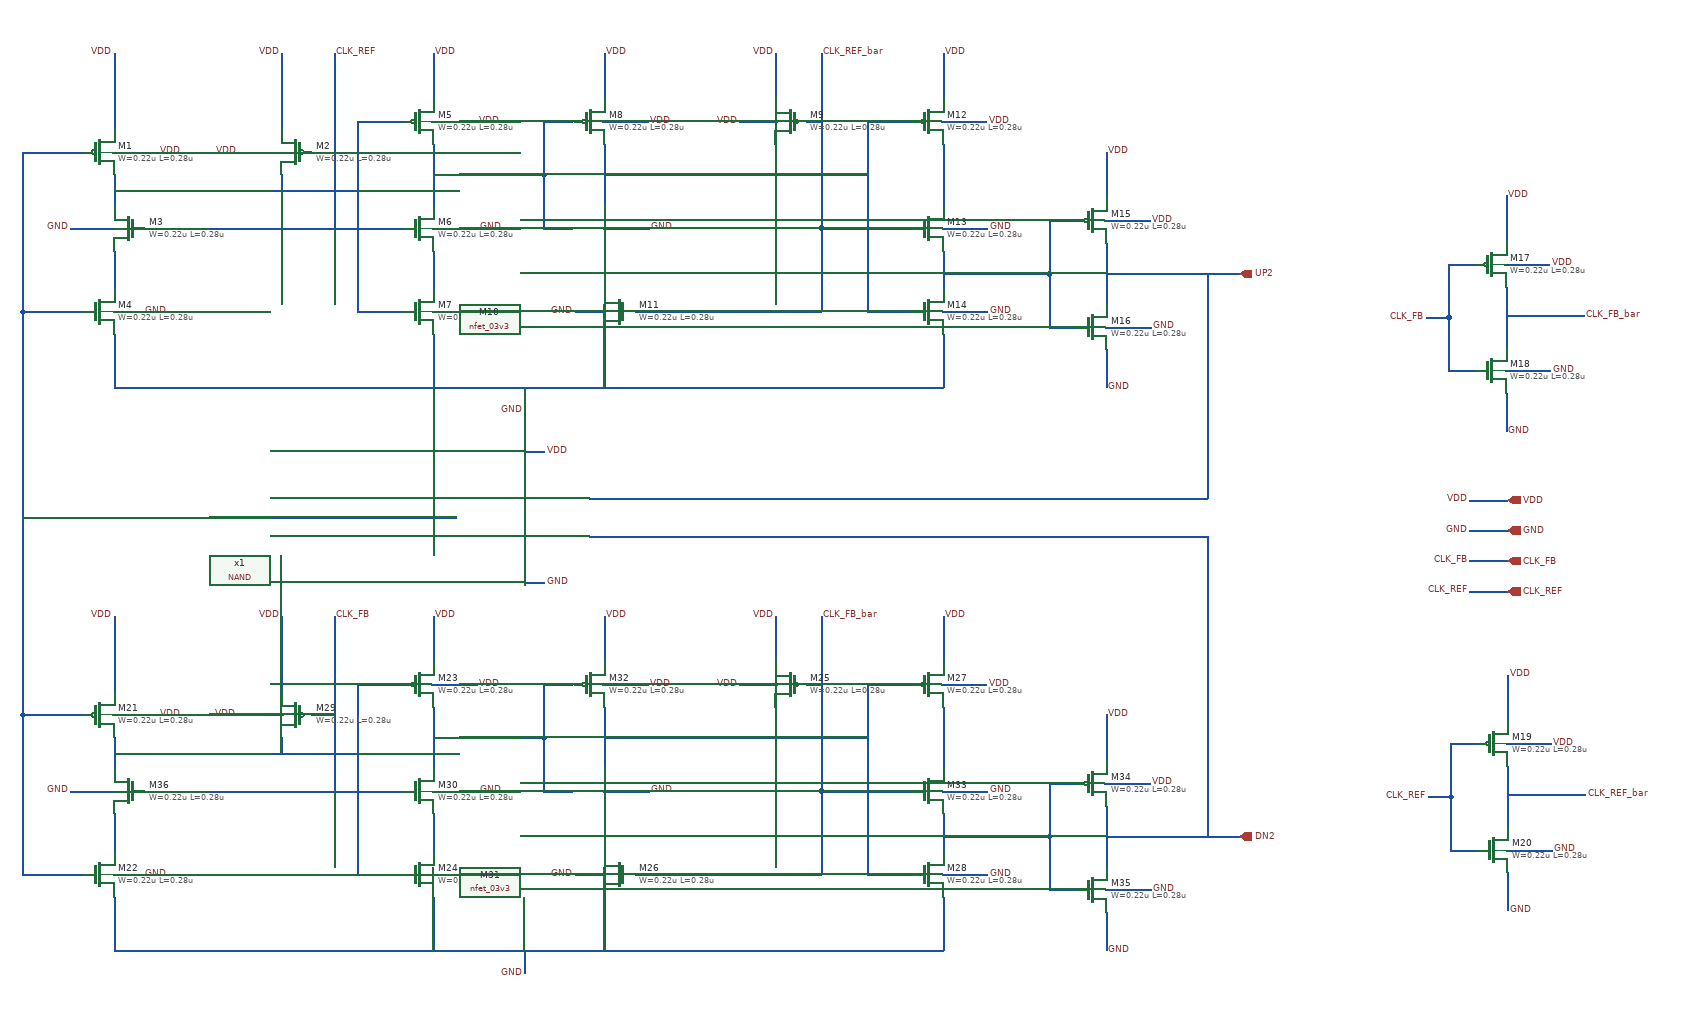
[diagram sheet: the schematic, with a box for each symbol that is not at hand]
v {xschem version=3.4.8RC file_version=1.3}
G {}
K {}
V {}
S {}
F {}
E {}
N -30 435 -30 475 {lab=#net1}
N -30 565 -30 585 {lab=#net2}
N -150 615 -70 615 {lab=#net3}
N -150 405 -150 615 {lab=#net3}
N -150 405 -70 405 {lab=#net3}
N 10 505 230 505 {lab=CLK_REF}
N 230 505 350 505 {lab=CLK_REF}
N 290 365 350 365 {lab=#net1}
N 390 395 390 475 {lab=#net4}
N 290 365 290 485 {lab=#net1}
N 290 515 290 565 {lab=#net1}
N -30 535 -30 565 {lab=#net2}
N 260 275 260 505 {lab=CLK_REF}
N 290 485 290 515 {lab=#net1}
N 290 565 290 615 {lab=#net1}
N 290 615 350 615 {lab=#net1}
N -30 645 -30 685 {lab=GND}
N 390 275 390 335 {lab=VDD}
N -30 275 -30 375 {lab=VDD}
N 390 535 390 585 {lab=#net5}
N 390 645 390 685 {lab=GND}
N 900 505 1020 505 {lab=CLK_REF_bar}
N 960 365 1020 365 {lab=#net6}
N 1060 395 1060 475 {lab=#net7}
N 960 365 960 485 {lab=#net6}
N 960 515 960 565 {lab=#net6}
N 900 275 900 505 {lab=CLK_REF_bar}
N 960 485 960 515 {lab=#net6}
N 960 565 960 615 {lab=#net6}
N 960 615 1020 615 {lab=#net6}
N 1060 275 1060 335 {lab=VDD}
N 1060 535 1060 585 {lab=#net8}
N 1060 645 1060 685 {lab=GND}
N 820 715 1060 715 {lab=GND}
N -30 715 820 715 {lab=GND}
N 390 685 390 715 {lab=GND}
N -30 685 -30 715 {lab=GND}
N 1060 685 1060 715 {lab=GND}
N 510 715 510 745 {lab=GND}
N 387.5 365 447.5 365 {lab=VDD}
N -32.5 405 27.5 405 {lab=VDD}
N -87.5 505 -27.5 505 {lab=GND}
N 388.75 505 448.75 505 {lab=GND}
N -31.25 615 8.75 615 {lab=GND}
N 388.75 615 438.75 615 {lab=GND}
N 792.5 365 842.5 365 {lab=VDD}
N 613.75 505 673.75 505 {lab=GND}
N 576.25 615 616.25 615 {lab=GND}
N 1057.5 365 1117.5 365 {lab=VDD}
N 1058.75 505 1118.75 505 {lab=GND}
N 1058.75 615 1118.75 615 {lab=GND}
N 1060 565 1170 565 {lab=#net8}
N -150 1145 -150 1355 {lab=#net3}
N -150 615 -150 1145 {lab=#net3}
N -150 885 420 885 {lab=#net3}
N 1170 565 1200 565 {lab=#net8}
N 1752.5 862.5 1802.5 862.5 {lab=VDD}
N 1752.5 902.5 1802.5 902.5 {lab=GND}
N 1752.5 942.5 1802.5 942.5 {lab=CLK_FB}
N 1752.5 982.5 1802.5 982.5 {lab=CLK_REF}
N -30 455 290 455 {lab=#net1}
N 190 435 190 455 {lab=#net1}
N 230 405 260 405 {lab=CLK_REF}
N 190 275 190 375 {lab=VDD}
N 133.75 405 193.75 405 {lab=VDD}
N 880 365 900 365 {lab=CLK_REF_bar}
N 615 275 615 335 {lab=VDD}
N 612.5 365 672.5 365 {lab=VDD}
N 535 365 572.5 365 {lab=#net4}
N 535 365 535 435 {lab=#net4}
N 615 395 615 472.5 {lab=#net6}
N 390 435 535 435 {lab=#net4}
N 535 435 535 505 {lab=#net4}
N 535 505 572.5 505 {lab=#net4}
N 615 435 960 435 {lab=#net6}
N 840 275 840 332.5 {lab=VDD}
N 840 395 840 435 {lab=#net6}
N 655 615 900 615 {lab=CLK_REF_bar}
N 615 645 615 715 {lab=GND}
N 615 535 615 585 {lab=#net9}
N 900 505 900 615 {lab=CLK_REF_bar}
N 1275 525 1275 605 {lab=UP2}
N 1275 405 1275 465 {lab=VDD}
N 1275 665 1275 715 {lab=GND}
N 1272.5 495 1332.5 495 {lab=VDD}
N 1273.75 635 1333.75 635 {lab=GND}
N 1200 495 1200 565 {lab=#net8}
N 1200 495 1235 495 {lab=#net8}
N 1200 565 1200 635 {lab=#net8}
N 1200 635 1235 635 {lab=#net8}
N 1275 565 1450 565 {lab=UP2}
N 1695 622.5 1725 622.5 {lab=CLK_FB}
N 1800 582.5 1800 662.5 {lab=CLK_FB_bar}
N 1800 462.5 1800 522.5 {lab=VDD}
N 1800 722.5 1800 772.5 {lab=GND}
N 1797.5 552.5 1857.5 552.5 {lab=VDD}
N 1798.75 692.5 1858.75 692.5 {lab=GND}
N 1725 552.5 1725 622.5 {lab=CLK_FB}
N 1725 552.5 1760 552.5 {lab=CLK_FB}
N 1725 622.5 1725 692.5 {lab=CLK_FB}
N 1725 692.5 1760 692.5 {lab=CLK_FB}
N 1800 620 1902.5 620 {lab=CLK_FB_bar}
N 1697.5 1252.5 1727.5 1252.5 {lab=CLK_REF}
N 1802.5 1212.5 1802.5 1292.5 {lab=CLK_REF_bar}
N 1802.5 1092.5 1802.5 1152.5 {lab=VDD}
N 1802.5 1352.5 1802.5 1402.5 {lab=GND}
N 1800 1182.5 1860 1182.5 {lab=VDD}
N 1801.25 1322.5 1861.25 1322.5 {lab=GND}
N 1727.5 1182.5 1727.5 1252.5 {lab=CLK_REF}
N 1727.5 1182.5 1762.5 1182.5 {lab=CLK_REF}
N 1727.5 1252.5 1727.5 1322.5 {lab=CLK_REF}
N 1727.5 1322.5 1762.5 1322.5 {lab=CLK_REF}
N 1802.5 1250 1905 1250 {lab=CLK_REF_bar}
N -30 1175 -30 1215 {lab=#net10}
N -30 1305 -30 1325 {lab=#net11}
N -150 1355 -70 1355 {lab=#net3}
N -150 1145 -70 1145 {lab=#net3}
N 10 1245 230 1245 {lab=CLK_FB}
N 230 1245 350 1245 {lab=CLK_FB}
N 290 1105 350 1105 {lab=#net10}
N 390 1135 390 1215 {lab=#net12}
N 290 1105 290 1225 {lab=#net10}
N 290 1255 290 1305 {lab=#net10}
N -30 1275 -30 1305 {lab=#net11}
N 260 1015 260 1245 {lab=CLK_FB}
N 290 1225 290 1255 {lab=#net10}
N 290 1305 290 1355 {lab=#net10}
N 290 1355 350 1355 {lab=#net10}
N -30 1385 -30 1425 {lab=GND}
N 390 1015 390 1075 {lab=VDD}
N -30 1015 -30 1115 {lab=VDD}
N 390 1275 390 1325 {lab=#net13}
N 390 1385 390 1425 {lab=GND}
N 900 1245 1020 1245 {lab=CLK_FB_bar}
N 960 1105 1020 1105 {lab=#net14}
N 1060 1135 1060 1215 {lab=#net15}
N 960 1105 960 1225 {lab=#net14}
N 960 1255 960 1305 {lab=#net14}
N 900 1015 900 1245 {lab=CLK_FB_bar}
N 960 1225 960 1255 {lab=#net14}
N 960 1305 960 1355 {lab=#net14}
N 960 1355 1020 1355 {lab=#net14}
N 1060 1015 1060 1075 {lab=VDD}
N 1060 1275 1060 1325 {lab=#net16}
N 1060 1385 1060 1425 {lab=GND}
N 820 1455 1060 1455 {lab=GND}
N -30 1455 820 1455 {lab=GND}
N 390 1425 390 1455 {lab=GND}
N -30 1425 -30 1455 {lab=GND}
N 1060 1425 1060 1455 {lab=GND}
N 510 1455 510 1485 {lab=GND}
N 387.5 1105 447.5 1105 {lab=VDD}
N -32.5 1145 27.5 1145 {lab=VDD}
N -87.5 1245 -27.5 1245 {lab=GND}
N 388.75 1245 448.75 1245 {lab=GND}
N -31.25 1355 8.75 1355 {lab=GND}
N 388.75 1355 438.75 1355 {lab=GND}
N 792.5 1105 842.5 1105 {lab=VDD}
N 613.75 1245 673.75 1245 {lab=GND}
N 576.25 1355 616.25 1355 {lab=GND}
N 1057.5 1105 1117.5 1105 {lab=VDD}
N 1058.75 1245 1118.75 1245 {lab=GND}
N 1058.75 1355 1118.75 1355 {lab=GND}
N 1060 1305 1170 1305 {lab=#net16}
N 1170 1305 1200 1305 {lab=#net16}
N -30 1195 290 1195 {lab=#net10}
N 190 1175 190 1195 {lab=#net10}
N 230 1145 260 1145 {lab=CLK_FB}
N 190 1015 190 1115 {lab=VDD}
N 132.5 1145 192.5 1145 {lab=VDD}
N 880 1105 900 1105 {lab=CLK_FB_bar}
N 615 1015 615 1075 {lab=VDD}
N 612.5 1105 672.5 1105 {lab=VDD}
N 535 1105 572.5 1105 {lab=#net12}
N 535 1105 535 1175 {lab=#net12}
N 615 1135 615 1212.5 {lab=#net14}
N 390 1175 535 1175 {lab=#net12}
N 535 1175 535 1245 {lab=#net12}
N 535 1245 572.5 1245 {lab=#net12}
N 615 1175 960 1175 {lab=#net14}
N 840 1015 840 1072.5 {lab=VDD}
N 840 1135 840 1175 {lab=#net14}
N 655 1355 900 1355 {lab=CLK_FB_bar}
N 615 1385 615 1455 {lab=GND}
N 615 1275 615 1325 {lab=#net17}
N 900 1245 900 1355 {lab=CLK_FB_bar}
N 1275 1265 1275 1345 {lab=DN2}
N 1275 1145 1275 1205 {lab=VDD}
N 1275 1405 1275 1455 {lab=GND}
N 1272.5 1235 1332.5 1235 {lab=VDD}
N 1273.75 1375 1333.75 1375 {lab=GND}
N 1200 1235 1200 1305 {lab=#net16}
N 1200 1235 1235 1235 {lab=#net16}
N 1200 1305 1200 1375 {lab=#net16}
N 1200 1375 1235 1375 {lab=#net16}
N 1275 1305 1450 1305 {lab=DN2}
N 511.25 798.75 536.25 798.75 {lab=VDD}
N 511.25 971.25 536.25 971.25 {lab=GND}
N 595 860 1407.5 860 {lab=UP2}
N 1407.5 565 1407.5 860 {lab=UP2}
N 595 910 1407.5 910 {lab=DN2}
N 1407.5 910 1407.5 1305 {lab=DN2}
C {symbols/pfet_03v3.sym} -50 405 0 0 {name=M1
L=0.28u
W=0.22u
nf=1
m=1
ad="'int((nf+1)/2) * W/nf * 0.18u'"
pd="'2*int((nf+1)/2) * (W/nf + 0.18u)'"
as="'int((nf+2)/2) * W/nf * 0.18u'"
ps="'2*int((nf+2)/2) * (W/nf + 0.18u)'"
nrd="'0.18u / W'" nrs="'0.18u / W'"
sa=0 sb=0 sd=0
model=pfet_03v3
spiceprefix=X
}
C {symbols/nfet_03v3.sym} -50 615 0 0 {name=M4
L=0.28u
W=0.22u
nf=1
m=1
ad="'int((nf+1)/2) * W/nf * 0.18u'"
pd="'2*int((nf+1)/2) * (W/nf + 0.18u)'"
as="'int((nf+2)/2) * W/nf * 0.18u'"
ps="'2*int((nf+2)/2) * (W/nf + 0.18u)'"
nrd="'0.18u / W'" nrs="'0.18u / W'"
sa=0 sb=0 sd=0
model=nfet_03v3
spiceprefix=X
}
C {symbols/pfet_03v3.sym} 370 365 0 0 {name=M5
L=0.28u
W=0.22u
nf=1
m=1
ad="'int((nf+1)/2) * W/nf * 0.18u'"
pd="'2*int((nf+1)/2) * (W/nf + 0.18u)'"
as="'int((nf+2)/2) * W/nf * 0.18u'"
ps="'2*int((nf+2)/2) * (W/nf + 0.18u)'"
nrd="'0.18u / W'" nrs="'0.18u / W'"
sa=0 sb=0 sd=0
model=pfet_03v3
spiceprefix=X
}
C {symbols/nfet_03v3.sym} 370 615 0 0 {name=M7
L=0.28u
W=0.22u
nf=1
m=1
ad="'int((nf+1)/2) * W/nf * 0.18u'"
pd="'2*int((nf+1)/2) * (W/nf + 0.18u)'"
as="'int((nf+2)/2) * W/nf * 0.18u'"
ps="'2*int((nf+2)/2) * (W/nf + 0.18u)'"
nrd="'0.18u / W'" nrs="'0.18u / W'"
sa=0 sb=0 sd=0
model=nfet_03v3
spiceprefix=X
}
C {symbols/pfet_03v3.sym} 860 365 0 1 {name=M9
L=0.28u
W=0.22u
nf=1
m=1
ad="'int((nf+1)/2) * W/nf * 0.18u'"
pd="'2*int((nf+1)/2) * (W/nf + 0.18u)'"
as="'int((nf+2)/2) * W/nf * 0.18u'"
ps="'2*int((nf+2)/2) * (W/nf + 0.18u)'"
nrd="'0.18u / W'" nrs="'0.18u / W'"
sa=0 sb=0 sd=0
model=pfet_03v3
spiceprefix=X
}
C {symbols/nfet_03v3.sym} 635 615 0 1 {name=M11
L=0.28u
W=0.22u
nf=1
m=1
ad="'int((nf+1)/2) * W/nf * 0.18u'"
pd="'2*int((nf+1)/2) * (W/nf + 0.18u)'"
as="'int((nf+2)/2) * W/nf * 0.18u'"
ps="'2*int((nf+2)/2) * (W/nf + 0.18u)'"
nrd="'0.18u / W'" nrs="'0.18u / W'"
sa=0 sb=0 sd=0
model=nfet_03v3
spiceprefix=X
}
C {symbols/pfet_03v3.sym} 1040 365 0 0 {name=M12
L=0.28u
W=0.22u
nf=1
m=1
ad="'int((nf+1)/2) * W/nf * 0.18u'"
pd="'2*int((nf+1)/2) * (W/nf + 0.18u)'"
as="'int((nf+2)/2) * W/nf * 0.18u'"
ps="'2*int((nf+2)/2) * (W/nf + 0.18u)'"
nrd="'0.18u / W'" nrs="'0.18u / W'"
sa=0 sb=0 sd=0
model=pfet_03v3
spiceprefix=X
}
C {symbols/nfet_03v3.sym} 1040 615 0 0 {name=M14
L=0.28u
W=0.22u
nf=1
m=1
ad="'int((nf+1)/2) * W/nf * 0.18u'"
pd="'2*int((nf+1)/2) * (W/nf + 0.18u)'"
as="'int((nf+2)/2) * W/nf * 0.18u'"
ps="'2*int((nf+2)/2) * (W/nf + 0.18u)'"
nrd="'0.18u / W'" nrs="'0.18u / W'"
sa=0 sb=0 sd=0
model=nfet_03v3
spiceprefix=X
}
C {lab_pin.sym} 260 275 0 1 {name=p53 sig_type=std_logic lab=CLK_REF}
C {lab_pin.sym} -30 275 0 0 {name=p54 sig_type=std_logic lab=VDD
}
C {lab_pin.sym} 390 275 0 1 {name=p55 sig_type=std_logic lab=VDD}
C {lab_pin.sym} 840 275 0 0 {name=p56 sig_type=std_logic lab=VDD}
C {lab_pin.sym} 900 275 0 1 {name=p57 sig_type=std_logic lab=CLK_REF_bar}
C {lab_pin.sym} 1060 275 0 1 {name=p58 sig_type=std_logic lab=VDD}
C {lab_pin.sym} 510 745 0 0 {name=p59 sig_type=std_logic lab=GND}
C {lab_pin.sym} 447.5 365 0 1 {name=p60 sig_type=std_logic lab=VDD}
C {lab_pin.sym} -87.5 505 0 0 {name=p61 sig_type=std_logic lab=GND}
C {lab_pin.sym} 27.5 405 0 1 {name=p62 sig_type=std_logic lab=VDD}
C {lab_pin.sym} 448.75 505 0 1 {name=p63 sig_type=std_logic lab=GND}
C {lab_pin.sym} 8.75 615 0 1 {name=p65 sig_type=std_logic lab=GND}
C {lab_pin.sym} 792.5 365 0 0 {name=p66 sig_type=std_logic lab=VDD}
C {lab_pin.sym} 673.75 505 0 1 {name=p67 sig_type=std_logic lab=GND}
C {lab_pin.sym} 438.75 615 0 1 {name=p68 sig_type=std_logic lab=GND}
C {lab_pin.sym} 576.25 615 0 0 {name=p70 sig_type=std_logic lab=GND}
C {lab_pin.sym} 1118.75 615 0 1 {name=p71 sig_type=std_logic lab=GND}
C {lab_pin.sym} 1118.75 505 0 1 {name=p72 sig_type=std_logic lab=GND}
C {lab_pin.sym} 1117.5 365 0 1 {name=p73 sig_type=std_logic lab=VDD}
C {opin.sym} 1450 565 0 0 {name=p74 lab=UP2}
C {ipin.sym} 1802.5 862.5 0 1 {name=p23 lab=VDD}
C {lab_pin.sym} 1752.5 862.5 0 0 {name=p24 sig_type=std_logic lab=VDD}
C {ipin.sym} 1802.5 902.5 0 1 {name=p25 lab=GND}
C {lab_pin.sym} 1752.5 902.5 0 0 {name=p26 sig_type=std_logic lab=GND}
C {ipin.sym} 1802.5 942.5 0 1 {name=p27 lab=CLK_FB}
C {lab_pin.sym} 1752.5 942.5 0 0 {name=p28 sig_type=std_logic lab=CLK_FB}
C {ipin.sym} 1802.5 982.5 0 1 {name=p51 lab=CLK_REF}
C {lab_pin.sym} 1752.5 982.5 0 0 {name=p52 sig_type=std_logic lab=CLK_REF}
C {symbols/pfet_03v3.sym} 210 405 0 1 {name=M2
L=0.28u
W=0.22u
nf=1
m=1
ad="'int((nf+1)/2) * W/nf * 0.18u'"
pd="'2*int((nf+1)/2) * (W/nf + 0.18u)'"
as="'int((nf+2)/2) * W/nf * 0.18u'"
ps="'2*int((nf+2)/2) * (W/nf + 0.18u)'"
nrd="'0.18u / W'" nrs="'0.18u / W'"
sa=0 sb=0 sd=0
model=pfet_03v3
spiceprefix=X
}
C {lab_pin.sym} 190 275 0 0 {name=p1 sig_type=std_logic lab=VDD
}
C {lab_pin.sym} 133.75 405 0 0 {name=p2 sig_type=std_logic lab=VDD}
C {symbols/nfet_03v3.sym} 370 505 0 0 {name=M6
L=0.28u
W=0.22u
nf=1
m=1
ad="'int((nf+1)/2) * W/nf * 0.18u'"
pd="'2*int((nf+1)/2) * (W/nf + 0.18u)'"
as="'int((nf+2)/2) * W/nf * 0.18u'"
ps="'2*int((nf+2)/2) * (W/nf + 0.18u)'"
nrd="'0.18u / W'" nrs="'0.18u / W'"
sa=0 sb=0 sd=0
model=nfet_03v3
spiceprefix=X
}
C {symbols/nfet_03v3.sym} 595 505 0 0 {name=M10
L=0.28u
W=0.22u
nf=1
m=1
ad="'int((nf+1)/2) * W/nf * 0.18u'"
pd="'2*int((nf+1)/2) * (W/nf + 0.18u)'"
as="'int((nf+2)/2) * W/nf * 0.18u'"
ps="'2*int((nf+2)/2) * (W/nf + 0.18u)'"
nrd="'0.18u / W'" nrs="'0.18u / W'"
sa=0 sb=0 sd=0
model=nfet_03v3
spiceprefix=X
}
C {symbols/pfet_03v3.sym} 595 365 0 0 {name=M8
L=0.28u
W=0.22u
nf=1
m=1
ad="'int((nf+1)/2) * W/nf * 0.18u'"
pd="'2*int((nf+1)/2) * (W/nf + 0.18u)'"
as="'int((nf+2)/2) * W/nf * 0.18u'"
ps="'2*int((nf+2)/2) * (W/nf + 0.18u)'"
nrd="'0.18u / W'" nrs="'0.18u / W'"
sa=0 sb=0 sd=0
model=pfet_03v3
spiceprefix=X
}
C {lab_pin.sym} 615 275 0 1 {name=p3 sig_type=std_logic lab=VDD}
C {lab_pin.sym} 672.5 365 0 1 {name=p4 sig_type=std_logic lab=VDD}
C {symbols/nfet_03v3.sym} 1040 505 0 0 {name=M13
L=0.28u
W=0.22u
nf=1
m=1
ad="'int((nf+1)/2) * W/nf * 0.18u'"
pd="'2*int((nf+1)/2) * (W/nf + 0.18u)'"
as="'int((nf+2)/2) * W/nf * 0.18u'"
ps="'2*int((nf+2)/2) * (W/nf + 0.18u)'"
nrd="'0.18u / W'" nrs="'0.18u / W'"
sa=0 sb=0 sd=0
model=nfet_03v3
spiceprefix=X
}
C {symbols/pfet_03v3.sym} 1255 495 0 0 {name=M15
L=0.28u
W=0.22u
nf=1
m=3
ad="'int((nf+1)/2) * W/nf * 0.18u'"
pd="'2*int((nf+1)/2) * (W/nf + 0.18u)'"
as="'int((nf+2)/2) * W/nf * 0.18u'"
ps="'2*int((nf+2)/2) * (W/nf + 0.18u)'"
nrd="'0.18u / W'" nrs="'0.18u / W'"
sa=0 sb=0 sd=0
model=pfet_03v3
spiceprefix=X
}
C {lab_pin.sym} 1333.75 635 0 1 {name=p5 sig_type=std_logic lab=GND}
C {lab_pin.sym} 1332.5 495 0 1 {name=p6 sig_type=std_logic lab=VDD}
C {symbols/nfet_03v3.sym} 1255 635 0 0 {name=M16
L=0.28u
W=0.22u
nf=1
m=1
ad="'int((nf+1)/2) * W/nf * 0.18u'"
pd="'2*int((nf+1)/2) * (W/nf + 0.18u)'"
as="'int((nf+2)/2) * W/nf * 0.18u'"
ps="'2*int((nf+2)/2) * (W/nf + 0.18u)'"
nrd="'0.18u / W'" nrs="'0.18u / W'"
sa=0 sb=0 sd=0
model=nfet_03v3
spiceprefix=X
}
C {lab_pin.sym} 1275 405 0 1 {name=p7 sig_type=std_logic lab=VDD}
C {lab_pin.sym} 1275 715 0 1 {name=p8 sig_type=std_logic lab=GND}
C {symbols/pfet_03v3.sym} 1780 552.5 0 0 {name=M17
L=0.28u
W=0.22u
nf=1
m=3
ad="'int((nf+1)/2) * W/nf * 0.18u'"
pd="'2*int((nf+1)/2) * (W/nf + 0.18u)'"
as="'int((nf+2)/2) * W/nf * 0.18u'"
ps="'2*int((nf+2)/2) * (W/nf + 0.18u)'"
nrd="'0.18u / W'" nrs="'0.18u / W'"
sa=0 sb=0 sd=0
model=pfet_03v3
spiceprefix=X
}
C {lab_pin.sym} 1858.75 692.5 0 1 {name=p9 sig_type=std_logic lab=GND}
C {lab_pin.sym} 1857.5 552.5 0 1 {name=p10 sig_type=std_logic lab=VDD}
C {symbols/nfet_03v3.sym} 1780 692.5 0 0 {name=M18
L=0.28u
W=0.22u
nf=1
m=1
ad="'int((nf+1)/2) * W/nf * 0.18u'"
pd="'2*int((nf+1)/2) * (W/nf + 0.18u)'"
as="'int((nf+2)/2) * W/nf * 0.18u'"
ps="'2*int((nf+2)/2) * (W/nf + 0.18u)'"
nrd="'0.18u / W'" nrs="'0.18u / W'"
sa=0 sb=0 sd=0
model=nfet_03v3
spiceprefix=X
}
C {lab_pin.sym} 1800 462.5 0 1 {name=p11 sig_type=std_logic lab=VDD}
C {lab_pin.sym} 1800 772.5 0 1 {name=p12 sig_type=std_logic lab=GND}
C {lab_pin.sym} 1695 622.5 0 0 {name=p13 sig_type=std_logic lab=CLK_FB}
C {lab_pin.sym} 1902.5 620 0 1 {name=p14 sig_type=std_logic lab=CLK_FB_bar}
C {symbols/pfet_03v3.sym} 1782.5 1182.5 0 0 {name=M19
L=0.28u
W=0.22u
nf=1
m=3
ad="'int((nf+1)/2) * W/nf * 0.18u'"
pd="'2*int((nf+1)/2) * (W/nf + 0.18u)'"
as="'int((nf+2)/2) * W/nf * 0.18u'"
ps="'2*int((nf+2)/2) * (W/nf + 0.18u)'"
nrd="'0.18u / W'" nrs="'0.18u / W'"
sa=0 sb=0 sd=0
model=pfet_03v3
spiceprefix=X
}
C {lab_pin.sym} 1861.25 1322.5 0 1 {name=p15 sig_type=std_logic lab=GND}
C {lab_pin.sym} 1860 1182.5 0 1 {name=p16 sig_type=std_logic lab=VDD}
C {symbols/nfet_03v3.sym} 1782.5 1322.5 0 0 {name=M20
L=0.28u
W=0.22u
nf=1
m=1
ad="'int((nf+1)/2) * W/nf * 0.18u'"
pd="'2*int((nf+1)/2) * (W/nf + 0.18u)'"
as="'int((nf+2)/2) * W/nf * 0.18u'"
ps="'2*int((nf+2)/2) * (W/nf + 0.18u)'"
nrd="'0.18u / W'" nrs="'0.18u / W'"
sa=0 sb=0 sd=0
model=nfet_03v3
spiceprefix=X
}
C {lab_pin.sym} 1802.5 1092.5 0 1 {name=p17 sig_type=std_logic lab=VDD}
C {lab_pin.sym} 1802.5 1402.5 0 1 {name=p18 sig_type=std_logic lab=GND}
C {lab_pin.sym} 1697.5 1252.5 0 0 {name=p19 sig_type=std_logic lab=CLK_REF}
C {lab_pin.sym} 1905 1250 0 1 {name=p20 sig_type=std_logic lab=CLK_REF_bar}
C {symbols/nfet_03v3.sym} -10 505 0 1 {name=M3
L=0.28u
W=0.22u
nf=1
m=1
ad="'int((nf+1)/2) * W/nf * 0.18u'"
pd="'2*int((nf+1)/2) * (W/nf + 0.18u)'"
as="'int((nf+2)/2) * W/nf * 0.18u'"
ps="'2*int((nf+2)/2) * (W/nf + 0.18u)'"
nrd="'0.18u / W'" nrs="'0.18u / W'"
sa=0 sb=0 sd=0
model=nfet_03v3
spiceprefix=X
}
C {symbols/pfet_03v3.sym} -50 1145 0 0 {name=M21
L=0.28u
W=0.22u
nf=1
m=1
ad="'int((nf+1)/2) * W/nf * 0.18u'"
pd="'2*int((nf+1)/2) * (W/nf + 0.18u)'"
as="'int((nf+2)/2) * W/nf * 0.18u'"
ps="'2*int((nf+2)/2) * (W/nf + 0.18u)'"
nrd="'0.18u / W'" nrs="'0.18u / W'"
sa=0 sb=0 sd=0
model=pfet_03v3
spiceprefix=X
}
C {symbols/nfet_03v3.sym} -50 1355 0 0 {name=M22
L=0.28u
W=0.22u
nf=1
m=1
ad="'int((nf+1)/2) * W/nf * 0.18u'"
pd="'2*int((nf+1)/2) * (W/nf + 0.18u)'"
as="'int((nf+2)/2) * W/nf * 0.18u'"
ps="'2*int((nf+2)/2) * (W/nf + 0.18u)'"
nrd="'0.18u / W'" nrs="'0.18u / W'"
sa=0 sb=0 sd=0
model=nfet_03v3
spiceprefix=X
}
C {symbols/pfet_03v3.sym} 370 1105 0 0 {name=M23
L=0.28u
W=0.22u
nf=1
m=1
ad="'int((nf+1)/2) * W/nf * 0.18u'"
pd="'2*int((nf+1)/2) * (W/nf + 0.18u)'"
as="'int((nf+2)/2) * W/nf * 0.18u'"
ps="'2*int((nf+2)/2) * (W/nf + 0.18u)'"
nrd="'0.18u / W'" nrs="'0.18u / W'"
sa=0 sb=0 sd=0
model=pfet_03v3
spiceprefix=X
}
C {symbols/nfet_03v3.sym} 370 1355 0 0 {name=M24
L=0.28u
W=0.22u
nf=1
m=1
ad="'int((nf+1)/2) * W/nf * 0.18u'"
pd="'2*int((nf+1)/2) * (W/nf + 0.18u)'"
as="'int((nf+2)/2) * W/nf * 0.18u'"
ps="'2*int((nf+2)/2) * (W/nf + 0.18u)'"
nrd="'0.18u / W'" nrs="'0.18u / W'"
sa=0 sb=0 sd=0
model=nfet_03v3
spiceprefix=X
}
C {symbols/pfet_03v3.sym} 860 1105 0 1 {name=M25
L=0.28u
W=0.22u
nf=1
m=1
ad="'int((nf+1)/2) * W/nf * 0.18u'"
pd="'2*int((nf+1)/2) * (W/nf + 0.18u)'"
as="'int((nf+2)/2) * W/nf * 0.18u'"
ps="'2*int((nf+2)/2) * (W/nf + 0.18u)'"
nrd="'0.18u / W'" nrs="'0.18u / W'"
sa=0 sb=0 sd=0
model=pfet_03v3
spiceprefix=X
}
C {symbols/nfet_03v3.sym} 635 1355 0 1 {name=M26
L=0.28u
W=0.22u
nf=1
m=1
ad="'int((nf+1)/2) * W/nf * 0.18u'"
pd="'2*int((nf+1)/2) * (W/nf + 0.18u)'"
as="'int((nf+2)/2) * W/nf * 0.18u'"
ps="'2*int((nf+2)/2) * (W/nf + 0.18u)'"
nrd="'0.18u / W'" nrs="'0.18u / W'"
sa=0 sb=0 sd=0
model=nfet_03v3
spiceprefix=X
}
C {symbols/pfet_03v3.sym} 1040 1105 0 0 {name=M27
L=0.28u
W=0.22u
nf=1
m=1
ad="'int((nf+1)/2) * W/nf * 0.18u'"
pd="'2*int((nf+1)/2) * (W/nf + 0.18u)'"
as="'int((nf+2)/2) * W/nf * 0.18u'"
ps="'2*int((nf+2)/2) * (W/nf + 0.18u)'"
nrd="'0.18u / W'" nrs="'0.18u / W'"
sa=0 sb=0 sd=0
model=pfet_03v3
spiceprefix=X
}
C {symbols/nfet_03v3.sym} 1040 1355 0 0 {name=M28
L=0.28u
W=0.22u
nf=1
m=1
ad="'int((nf+1)/2) * W/nf * 0.18u'"
pd="'2*int((nf+1)/2) * (W/nf + 0.18u)'"
as="'int((nf+2)/2) * W/nf * 0.18u'"
ps="'2*int((nf+2)/2) * (W/nf + 0.18u)'"
nrd="'0.18u / W'" nrs="'0.18u / W'"
sa=0 sb=0 sd=0
model=nfet_03v3
spiceprefix=X
}
C {lab_pin.sym} 260 1015 0 1 {name=p21 sig_type=std_logic lab=CLK_FB}
C {lab_pin.sym} -30 1015 0 0 {name=p22 sig_type=std_logic lab=VDD
}
C {lab_pin.sym} 390 1015 0 1 {name=p29 sig_type=std_logic lab=VDD}
C {lab_pin.sym} 840 1015 0 0 {name=p30 sig_type=std_logic lab=VDD}
C {lab_pin.sym} 900 1015 0 1 {name=p31 sig_type=std_logic lab=CLK_FB_bar}
C {lab_pin.sym} 1060 1015 0 1 {name=p32 sig_type=std_logic lab=VDD}
C {lab_pin.sym} 510 1485 0 0 {name=p33 sig_type=std_logic lab=GND}
C {lab_pin.sym} 447.5 1105 0 1 {name=p34 sig_type=std_logic lab=VDD}
C {lab_pin.sym} -87.5 1245 0 0 {name=p35 sig_type=std_logic lab=GND}
C {lab_pin.sym} 27.5 1145 0 1 {name=p36 sig_type=std_logic lab=VDD}
C {lab_pin.sym} 448.75 1245 0 1 {name=p37 sig_type=std_logic lab=GND}
C {lab_pin.sym} 8.75 1355 0 1 {name=p38 sig_type=std_logic lab=GND}
C {lab_pin.sym} 792.5 1105 0 0 {name=p39 sig_type=std_logic lab=VDD}
C {lab_pin.sym} 673.75 1245 0 1 {name=p40 sig_type=std_logic lab=GND}
C {lab_pin.sym} 438.75 1355 0 1 {name=p41 sig_type=std_logic lab=GND}
C {lab_pin.sym} 576.25 1355 0 0 {name=p42 sig_type=std_logic lab=GND}
C {lab_pin.sym} 1118.75 1355 0 1 {name=p43 sig_type=std_logic lab=GND}
C {lab_pin.sym} 1118.75 1245 0 1 {name=p44 sig_type=std_logic lab=GND}
C {lab_pin.sym} 1117.5 1105 0 1 {name=p45 sig_type=std_logic lab=VDD}
C {opin.sym} 1450 1305 0 0 {name=p46 lab=DN2}
C {symbols/pfet_03v3.sym} 210 1145 0 1 {name=M29
L=0.28u
W=0.22u
nf=1
m=1
ad="'int((nf+1)/2) * W/nf * 0.18u'"
pd="'2*int((nf+1)/2) * (W/nf + 0.18u)'"
as="'int((nf+2)/2) * W/nf * 0.18u'"
ps="'2*int((nf+2)/2) * (W/nf + 0.18u)'"
nrd="'0.18u / W'" nrs="'0.18u / W'"
sa=0 sb=0 sd=0
model=pfet_03v3
spiceprefix=X
}
C {lab_pin.sym} 190 1015 0 0 {name=p47 sig_type=std_logic lab=VDD
}
C {lab_pin.sym} 132.5 1145 0 0 {name=p48 sig_type=std_logic lab=VDD}
C {symbols/nfet_03v3.sym} 370 1245 0 0 {name=M30
L=0.28u
W=0.22u
nf=1
m=1
ad="'int((nf+1)/2) * W/nf * 0.18u'"
pd="'2*int((nf+1)/2) * (W/nf + 0.18u)'"
as="'int((nf+2)/2) * W/nf * 0.18u'"
ps="'2*int((nf+2)/2) * (W/nf + 0.18u)'"
nrd="'0.18u / W'" nrs="'0.18u / W'"
sa=0 sb=0 sd=0
model=nfet_03v3
spiceprefix=X
}
C {symbols/nfet_03v3.sym} 595 1245 0 0 {name=M31
L=0.28u
W=0.22u
nf=1
m=1
ad="'int((nf+1)/2) * W/nf * 0.18u'"
pd="'2*int((nf+1)/2) * (W/nf + 0.18u)'"
as="'int((nf+2)/2) * W/nf * 0.18u'"
ps="'2*int((nf+2)/2) * (W/nf + 0.18u)'"
nrd="'0.18u / W'" nrs="'0.18u / W'"
sa=0 sb=0 sd=0
model=nfet_03v3
spiceprefix=X
}
C {symbols/pfet_03v3.sym} 595 1105 0 0 {name=M32
L=0.28u
W=0.22u
nf=1
m=1
ad="'int((nf+1)/2) * W/nf * 0.18u'"
pd="'2*int((nf+1)/2) * (W/nf + 0.18u)'"
as="'int((nf+2)/2) * W/nf * 0.18u'"
ps="'2*int((nf+2)/2) * (W/nf + 0.18u)'"
nrd="'0.18u / W'" nrs="'0.18u / W'"
sa=0 sb=0 sd=0
model=pfet_03v3
spiceprefix=X
}
C {lab_pin.sym} 615 1015 0 1 {name=p49 sig_type=std_logic lab=VDD}
C {lab_pin.sym} 672.5 1105 0 1 {name=p50 sig_type=std_logic lab=VDD}
C {symbols/nfet_03v3.sym} 1040 1245 0 0 {name=M33
L=0.28u
W=0.22u
nf=1
m=1
ad="'int((nf+1)/2) * W/nf * 0.18u'"
pd="'2*int((nf+1)/2) * (W/nf + 0.18u)'"
as="'int((nf+2)/2) * W/nf * 0.18u'"
ps="'2*int((nf+2)/2) * (W/nf + 0.18u)'"
nrd="'0.18u / W'" nrs="'0.18u / W'"
sa=0 sb=0 sd=0
model=nfet_03v3
spiceprefix=X
}
C {symbols/pfet_03v3.sym} 1255 1235 0 0 {name=M34
L=0.28u
W=0.22u
nf=1
m=3
ad="'int((nf+1)/2) * W/nf * 0.18u'"
pd="'2*int((nf+1)/2) * (W/nf + 0.18u)'"
as="'int((nf+2)/2) * W/nf * 0.18u'"
ps="'2*int((nf+2)/2) * (W/nf + 0.18u)'"
nrd="'0.18u / W'" nrs="'0.18u / W'"
sa=0 sb=0 sd=0
model=pfet_03v3
spiceprefix=X
}
C {lab_pin.sym} 1333.75 1375 0 1 {name=p64 sig_type=std_logic lab=GND}
C {lab_pin.sym} 1332.5 1235 0 1 {name=p69 sig_type=std_logic lab=VDD}
C {symbols/nfet_03v3.sym} 1255 1375 0 0 {name=M35
L=0.28u
W=0.22u
nf=1
m=1
ad="'int((nf+1)/2) * W/nf * 0.18u'"
pd="'2*int((nf+1)/2) * (W/nf + 0.18u)'"
as="'int((nf+2)/2) * W/nf * 0.18u'"
ps="'2*int((nf+2)/2) * (W/nf + 0.18u)'"
nrd="'0.18u / W'" nrs="'0.18u / W'"
sa=0 sb=0 sd=0
model=nfet_03v3
spiceprefix=X
}
C {lab_pin.sym} 1275 1145 0 1 {name=p75 sig_type=std_logic lab=VDD}
C {lab_pin.sym} 1275 1455 0 1 {name=p76 sig_type=std_logic lab=GND}
C {symbols/nfet_03v3.sym} -10 1245 0 1 {name=M36
L=0.28u
W=0.22u
nf=1
m=1
ad="'int((nf+1)/2) * W/nf * 0.18u'"
pd="'2*int((nf+1)/2) * (W/nf + 0.18u)'"
as="'int((nf+2)/2) * W/nf * 0.18u'"
ps="'2*int((nf+2)/2) * (W/nf + 0.18u)'"
nrd="'0.18u / W'" nrs="'0.18u / W'"
sa=0 sb=0 sd=0
model=nfet_03v3
spiceprefix=X
}
C {NAND.sym} 410 895 0 0 {name=x1}
C {lab_pin.sym} 536.25 798.75 0 1 {name=p77 sig_type=std_logic lab=VDD}
C {lab_pin.sym} 536.25 971.25 0 1 {name=p78 sig_type=std_logic lab=GND}
